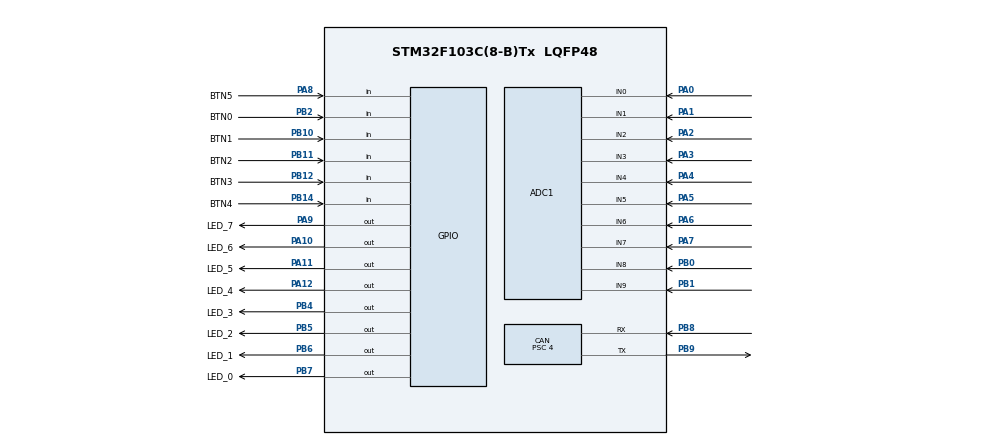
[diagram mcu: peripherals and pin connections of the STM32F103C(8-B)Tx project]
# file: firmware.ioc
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ADC1.Channel-0\#ChannelRegularConversion=ADC_CHANNEL_0
ADC1.Channel-1\#ChannelRegularConversion=ADC_CHANNEL_1
ADC1.Channel-10\#ChannelRegularConversion=ADC_CHANNEL_TEMPSENSOR
ADC1.Channel-2\#ChannelRegularConversion=ADC_CHANNEL_2
ADC1.Channel-3\#ChannelRegularConversion=ADC_CHANNEL_3
ADC1.Channel-4\#ChannelRegularConversion=ADC_CHANNEL_4
ADC1.Channel-5\#ChannelRegularConversion=ADC_CHANNEL_5
ADC1.Channel-6\#ChannelRegularConversion=ADC_CHANNEL_6
ADC1.Channel-7\#ChannelRegularConversion=ADC_CHANNEL_7
ADC1.Channel-8\#ChannelRegularConversion=ADC_CHANNEL_8
ADC1.Channel-9\#ChannelRegularConversion=ADC_CHANNEL_9
ADC1.NbrOfConversion=11
ADC1.NbrOfConversionFlag=1
ADC1.Rank-0\#ChannelRegularConversion=1
ADC1.Rank-1\#ChannelRegularConversion=2
ADC1.Rank-10\#ChannelRegularConversion=11
ADC1.Rank-2\#ChannelRegularConversion=3
ADC1.Rank-3\#ChannelRegularConversion=4
ADC1.Rank-4\#ChannelRegularConversion=5
ADC1.Rank-5\#ChannelRegularConversion=6
ADC1.Rank-6\#ChannelRegularConversion=7
ADC1.Rank-7\#ChannelRegularConversion=8
ADC1.Rank-8\#ChannelRegularConversion=9
ADC1.Rank-9\#ChannelRegularConversion=10
ADC1.SamplingTime-0\#ChannelRegularConversion=ADC_SAMPLETIME_71CYCLES_5
ADC1.SamplingTime-1\#ChannelRegularConversion=ADC_SAMPLETIME_71CYCLES_5
ADC1.SamplingTime-10\#ChannelRegularConversion=ADC_SAMPLETIME_239CYCLES_5
ADC1.SamplingTime-2\#ChannelRegularConversion=ADC_SAMPLETIME_71CYCLES_5
ADC1.SamplingTime-3\#ChannelRegularConversion=ADC_SAMPLETIME_71CYCLES_5
ADC1.SamplingTime-4\#ChannelRegularConversion=ADC_SAMPLETIME_71CYCLES_5
ADC1.SamplingTime-5\#ChannelRegularConversion=ADC_SAMPLETIME_71CYCLES_5
ADC1.SamplingTime-6\#ChannelRegularConversion=ADC_SAMPLETIME_71CYCLES_5
ADC1.SamplingTime-7\#ChannelRegularConversion=ADC_SAMPLETIME_71CYCLES_5
ADC1.SamplingTime-8\#ChannelRegularConversion=ADC_SAMPLETIME_71CYCLES_5
ADC1.SamplingTime-9\#ChannelRegularConversion=ADC_SAMPLETIME_71CYCLES_5
ADC1.master=1
CAN.BS1=CAN_BS1_11TQ
CAN.BS2=CAN_BS2_4TQ
CAN.CalculateBaudRate=500000
CAN.CalculateTimeBit=2000
CAN.CalculateTimeQuantum=125.0
CAN.Mode=CAN_MODE_NORMAL
CAN.NART=ENABLE
CAN.Prescaler=4
Dma.ADC1.0.Direction=DMA_PERIPH_TO_MEMORY
Dma.ADC1.0.Instance=DMA1_Channel1
Dma.ADC1.0.MemDataAlignment=DMA_MDATAALIGN_HALFWORD
Dma.ADC1.0.MemInc=DMA_MINC_ENABLE
Dma.ADC1.0.Mode=DMA_NORMAL
Dma.ADC1.0.PeriphDataAlignment=DMA_PDATAALIGN_HALFWORD
Dma.ADC1.0.PeriphInc=DMA_PINC_DISABLE
Dma.ADC1.0.Priority=DMA_PRIORITY_LOW
Dma.Request0=ADC1
Dma.Request1=TIM2_UP
Dma.Request2=TIM2_CH1
Dma.Request3=TIM2_CH2/CH4
Dma.TIM2_CH1.2.Direction=DMA_MEMORY_TO_PERIPH
Dma.TIM2_CH1.2.Instance=DMA1_Channel5
Dma.TIM2_CH1.2.MemDataAlignment=DMA_MDATAALIGN_HALFWORD
Dma.TIM2_CH1.2.MemInc=DMA_MINC_ENABLE
Dma.TIM2_CH1.2.Mode=DMA_NORMAL
Dma.TIM2_CH1.2.PeriphDataAlignment=DMA_PDATAALIGN_HALFWORD
Dma.TIM2_CH1.2.PeriphInc=DMA_PINC_DISABLE
Dma.TIM2_CH1.2.Priority=DMA_PRIORITY_VERY_HIGH
Dma.TIM2_CH2/CH4.3.Direction=DMA_MEMORY_TO_PERIPH
Dma.TIM2_CH2/CH4.3.Instance=DMA1_Channel7
Dma.TIM2_CH2/CH4.3.MemDataAlignment=DMA_MDATAALIGN_HALFWORD
Dma.TIM2_CH2/CH4.3.MemInc=DMA_MINC_DISABLE
Dma.TIM2_CH2/CH4.3.Mode=DMA_NORMAL
Dma.TIM2_CH2/CH4.3.PeriphDataAlignment=DMA_PDATAALIGN_HALFWORD
Dma.TIM2_CH2/CH4.3.PeriphInc=DMA_PINC_DISABLE
Dma.TIM2_CH2/CH4.3.Priority=DMA_PRIORITY_VERY_HIGH
Dma.TIM2_UP.1.Direction=DMA_MEMORY_TO_PERIPH
Dma.TIM2_UP.1.Instance=DMA1_Channel2
Dma.TIM2_UP.1.MemDataAlignment=DMA_MDATAALIGN_HALFWORD
Dma.TIM2_UP.1.MemInc=DMA_MINC_DISABLE
Dma.TIM2_UP.1.Mode=DMA_NORMAL
Dma.TIM2_UP.1.PeriphDataAlignment=DMA_PDATAALIGN_HALFWORD
Dma.TIM2_UP.1.PeriphInc=DMA_PINC_DISABLE
Dma.TIM2_UP.1.Priority=DMA_PRIORITY_VERY_HIGH
Mcu.Family=STM32F1
Mcu.Name=STM32F103C(8-B)Tx
Mcu.Package=LQFP48
NVIC.DMA1_Channel1_IRQn=true\:0\:0\:false\:false\:true\:false\:true\:true
NVIC.DMA1_Channel2_IRQn=true\:0\:0\:false\:false\:true\:false\:true\:true
NVIC.DMA1_Channel5_IRQn=true\:0\:0\:false\:false\:true\:false\:true\:true
NVIC.DMA1_Channel7_IRQn=true\:0\:0\:false\:false\:true\:false\:true\:true
NVIC.PriorityGroup=NVIC_PRIORITYGROUP_4
NVIC.USB_LP_CAN1_RX0_IRQn=true\:0\:0\:false\:false\:true\:true\:true\:true
PA0-WKUP.Signal=ADCx_IN0
PA1.Signal=ADCx_IN1
PA10.GPIO_Label=LED_6
PA10.GPIO_Speed=GPIO_SPEED_FREQ_HIGH
PA10.Signal=GPIO_Output
PA11.GPIO_Label=LED_5
PA11.GPIO_Speed=GPIO_SPEED_FREQ_HIGH
PA11.Signal=GPIO_Output
PA12.GPIO_Label=LED_4
PA12.GPIO_Speed=GPIO_SPEED_FREQ_HIGH
PA12.Signal=GPIO_Output
PA13.Mode=Trace_Asynchronous_SW
PA13.Signal=SYS_JTMS-SWDIO
PA14.Mode=Trace_Asynchronous_SW
PA14.Signal=SYS_JTCK-SWCLK
PA2.Signal=ADCx_IN2
PA3.Signal=ADCx_IN3
PA4.Signal=ADCx_IN4
PA5.Signal=ADCx_IN5
PA6.Signal=ADCx_IN6
PA7.Signal=ADCx_IN7
PA8.GPIO_Label=BTN5
PA8.Signal=GPIO_Input
PA9.GPIO_Label=LED_7
PA9.GPIO_Speed=GPIO_SPEED_FREQ_HIGH
PA9.Signal=GPIO_Output
PB0.Signal=ADCx_IN8
PB1.Signal=ADCx_IN9
PB10.GPIO_Label=BTN1
PB10.Signal=GPIO_Input
PB11.GPIO_Label=BTN2
PB11.Signal=GPIO_Input
PB12.GPIO_Label=BTN3
PB12.Signal=GPIO_Input
PB14.GPIO_Label=BTN4
PB14.Signal=GPIO_Input
PB2.GPIO_Label=BTN0
PB2.Signal=GPIO_Input
PB3.Mode=Trace_Asynchronous_SW
PB3.Signal=SYS_JTDO-TRACESWO
PB4.GPIO_Label=LED_3
PB4.GPIO_Speed=GPIO_SPEED_FREQ_HIGH
PB4.Signal=GPIO_Output
PB5.GPIO_Label=LED_2
PB5.GPIO_Speed=GPIO_SPEED_FREQ_HIGH
PB5.Signal=GPIO_Output
PB6.GPIO_Label=LED_1
PB6.GPIO_Speed=GPIO_SPEED_FREQ_HIGH
PB6.Signal=GPIO_Output
PB7.GPIO_Label=LED_0
PB7.GPIO_Speed=GPIO_SPEED_FREQ_HIGH
PB7.Signal=GPIO_Output
PB8.GPIO_Mode=GPIO_MODE_INPUT
PB8.GPIO_PuPd=GPIO_NOPULL
PB8.Mode=CAN_Activate
PB8.Signal=CAN_RX
PB9.Mode=CAN_Activate
PB9.Signal=CAN_TX
PD0-OSC_IN.Mode=HSE-External-Oscillator
PD0-OSC_IN.Signal=RCC_OSC_IN
PD1-OSC_OUT.Mode=HSE-External-Oscillator
PD1-OSC_OUT.Signal=RCC_OSC_OUT
ProjectManager.HeapSize=0x200
ProjectManager.StackSize=0x400
ProjectManager.TargetToolchain=Makefile
RCC.ADCPresc=RCC_ADCPCLK2_DIV6
RCC.AHBFreq_Value=128000000
RCC.APB1CLKDivider=RCC_HCLK_DIV4
RCC.APB1Freq_Value=32000000
RCC.APB1TimFreq_Value=64000000
RCC.APB2CLKDivider=RCC_HCLK_DIV2
RCC.APB2Freq_Value=64000000
RCC.APB2TimFreq_Value=128000000
RCC.HCLKFreq_Value=128000000
RCC.PLLMUL=RCC_PLL_MUL16
RCC.PLLSourceVirtual=RCC_PLLSOURCE_HSE
RCC.SYSCLKFreq_VALUE=128000000
RCC.SYSCLKSource=RCC_SYSCLKSOURCE_PLLCLK
RCC.USBFreq_Value=128000000
SH.ADCx_IN0.0=ADC1_IN0,IN0
SH.ADCx_IN1.0=ADC1_IN1,IN1
SH.ADCx_IN2.0=ADC1_IN2,IN2
SH.ADCx_IN3.0=ADC1_IN3,IN3
SH.ADCx_IN4.0=ADC1_IN4,IN4
SH.ADCx_IN5.0=ADC1_IN5,IN5
SH.ADCx_IN6.0=ADC1_IN6,IN6
SH.ADCx_IN7.0=ADC1_IN7,IN7
SH.ADCx_IN8.0=ADC1_IN8,IN8
SH.ADCx_IN9.0=ADC1_IN9,IN9
TIM2.AutoReloadPreload=TIM_AUTORELOAD_PRELOAD_ENABLE
TIM2.Channel-PWM\ Generation1\ No\ Output=TIM_CHANNEL_1
TIM2.Channel-PWM\ Generation2\ No\ Output=TIM_CHANNEL_2
TIM2.Period=76
TIM2.Pulse-PWM\ Generation1\ No\ Output=10
TIM2.Pulse-PWM\ Generation2\ No\ Output=41
VP_ADC1_TempSens_Input.Mode=IN-TempSens
VP_TIM2_VS_ClockSourceINT.Mode=Internal
VP_TIM2_VS_no_output1.Mode=PWM Generation1 No Output
VP_TIM2_VS_no_output2.Mode=PWM Generation2 No Output
board=custom

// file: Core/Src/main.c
/* USER CODE BEGIN Header */
/**
  ******************************************************************************
  * @file           : main.c
  * @brief          : Main program body - EV Dashboard 2026
  ******************************************************************************
  * @attention
  *
  * Copyright (c) 2023 STMicroelectronics.
  * All rights reserved.
  *
  * This software is licensed under terms that can be found in the LICENSE file
  * in the root directory of this software component.
  * If no LICENSE file comes with this software, it is provided AS-IS.
  *
  ******************************************************************************
  */
/* USER CODE END Header */
#include "main.h"

/* USER CODE BEGIN Includes */

#include <math.h>

#include "ws2812.h"
#include "display.h"
#include "auto_brightness.h"
#include "dial.h"
#include "ui.h"
#include "can-ids/CAN.h"
/* USER CODE END Includes */

ADC_HandleTypeDef hadc1;
DMA_HandleTypeDef hdma_adc1;

CAN_HandleTypeDef hcan;

TIM_HandleTypeDef htim2;
DMA_HandleTypeDef hdma_tim2_up;
DMA_HandleTypeDef hdma_tim2_ch1;
DMA_HandleTypeDef hdma_tim2_ch2_ch4;

/* USER CODE BEGIN PV */

volatile uint16_t adc_buffer[2][11];
volatile uint8_t adc_buffer_idx = 0;
volatile uint8_t adc_ready = 1;
struct CarState carState;
/* USER CODE END PV */

void SystemClock_Config(void);
static void MX_GPIO_Init(void);
static void MX_DMA_Init(void);
static void MX_CAN_Init(void);
static void MX_ADC1_Init(void);
static void MX_TIM2_Init(void);
/* USER CODE BEGIN PFP */
extern void HAL_ADC_ConvCpltCallback(ADC_HandleTypeDef* hadc);
/* USER CODE END PFP */

/* USER CODE BEGIN 0 */

void can_irq(CAN_HandleTypeDef *pcan) {
  CAN_RxHeaderTypeDef msg;
    uint8_t data[8];
    HAL_CAN_GetRxMessage(pcan, CAN_RX_FIFO0, &msg, data);

    if (msg.IDE == CAN_ID_STD) {
        switch (msg.StdId) {
            // ===== INVERTER MESSAGES =====

            case INVERTER_HIGH_SPEED_ID:
                // High-speed frame (3ms) - most important data
                carState.commanded_torque = read_field_i16(&INVERTER_HIGH_SPEED_commanded_torque, data);
                carState.torque_feedback = read_field_i16(&INVERTER_HIGH_SPEED_torque_feedback, data);
                carState.motor_speed = read_field_i16(&INVERTER_HIGH_SPEED_motor_speed, data);
                carState.dc_bus_voltage = read_field_i16(&INVERTER_HIGH_SPEED_dc_bus_voltage, data);
                carState.last_inverter_msg_tick = HAL_GetTick();
                break;

            case INVERTER_TEMP_1_ID:
                // IGBT temperatures
                carState.igbt_a_temp = read_field_i16(&INVERTER_TEMP_1_IGBT_A_temp, data);
                carState.igbt_b_temp = read_field_i16(&INVERTER_TEMP_1_IGBT_B_temp, data);
                carState.igbt_c_temp = read_field_i16(&INVERTER_TEMP_1_IGBT_C_temp, data);
                carState.gate_driver_temp = read_field_i16(&INVERTER_TEMP_1_gate_driver_temp, data);
                break;

            case INVERTER_TEMP_2_ID:
                // Control board and RTD temperatures
                carState.control_board_temp = read_field_i16(&INVERTER_TEMP_2_control_board_temp, data);
                // RTD temps available if needed
                break;

            case INVERTER_TEMP_3_ID:
                // Motor temperature
                carState.motor_temp = read_field_i16(&INVERTER_TEMP_3_motor_temp, data);
                break;

            case INVERTER_CURRENT_ID:
                // DC bus current
                carState.dc_bus_current = read_field_i16(&INVERTER_CURRENT_dc_bus, data);
                break;

            case INVERTER_INTERNAL_VOLTAGE_ID:
                // 12V (GLV) voltage
                carState.glv_voltage = read_field_i16(&INVERTER_INTERNAL_VOLTAGE_glv_voltage, data);
                break;

            case INVERTER_INTERNAL_STATES_ID:
                // Inverter state machine
                carState.vsm_state = read_field_u8(&INVERTER_INTERNAL_STATES_vsm_state, data);
                carState.inverter_state = read_field_u8(&INVERTER_INTERNAL_STATES_inverter_state, data);
                carState.inverter_enable = read_field_u8(&INVERTER_INTERNAL_STATES_enable_state, data);
                carState.direction_command = read_field_u8(&INVERTER_INTERNAL_STATES_direction_command, data);
                carState.run_mode = read_field_u8(&INVERTER_INTERNAL_STATES_run_mode, data);
                break;

            case INVERTER_FAULT_CODES_ID:
                // Fault codes
                carState.post_fault = read_field_u32(&INVERTER_FAULT_CODES_POST_fault, data);
                carState.run_fault = read_field_u32(&INVERTER_FAULT_CODES_run_fault, data);
                break;

                // ===== ORION BMS MESSAGES =====

            case BMS_PACK_STATUS_ID:
                // Pack SOC, Voltage, Current
                carState.soc_percent = read_field_u8(&BMS_PACK_STATUS_pack_soc, data);
                carState.pack_voltage = read_field_u16(&BMS_PACK_STATUS_pack_voltage, data);
                carState.pack_current = read_field_i16(&BMS_PACK_STATUS_pack_current, data);
                carState.last_bms_msg_tick = HAL_GetTick();
                break;

            case BMS_TEMPS_ID:
                // Battery temperatures
                carState.pack_temp_max = read_field_i16(&BMS_TEMPS_max_cell_temp, data);
                carState.pack_temp_min = read_field_i16(&BMS_TEMPS_min_cell_temp, data);
                break;

            case BMS_STATUS_ID:
                // BMS status and limits
                carState.bms_fault_code = read_field_u8(&BMS_STATUS_fault_code, data);
                // Pack discharge/charge limits available here if needed
                break;

            // ===== DASHBOARD INPUTS (from steering wheel) =====

            case DASHBOARD_0_ID:
                carState.dial_pos[0] = read_field_u8(&DASHBOARD_0_dial_0, data);
                carState.dial_pos[1] = read_field_u8(&DASHBOARD_0_dial_1, data);
                break;

            // ===== BOOTLOADER =====

            case BOOTLOADER_ID:
                // Reset to bootloader if requested
                __NVIC_SystemReset();
                break;

            default:
                // Unknown message

        break;
      }
  }
}

void HAL_ADC_ConvCpltCallback(ADC_HandleTypeDef* hadc){
  /* This is called after the conversion is completed */
  adc_buffer_idx = (adc_buffer_idx + 1) % 2;
  adc_ready = 1;
}

/* USER CODE END 0 */

int main(void)
{
  /* USER CODE BEGIN 1 */
  // relocate vector table to work with bootloader
	SCB->VTOR = (uint32_t)0x08003000;
  /* USER CODE END 1 */

  /* MCU Configuration--------------------------------------------------------*/

  /* Reset of all peripherals, Initializes the Flash interface and the Systick. */
  HAL_Init();

  /* Configure the system clock */
  SystemClock_Config();

  /* Initialize all configured peripherals */
  MX_GPIO_Init();
  MX_DMA_Init();
  MX_CAN_Init();
  MX_ADC1_Init();
  MX_TIM2_Init();
  /* USER CODE BEGIN 2 */

  HAL_ADCEx_Calibration_Start(&hadc1);

  // Initialize car state to safe defaults
    carState.soc_percent = 50;  // Will be updated by BMS
    carState.drive_mode = 1;    // Normal mode
    carState.last_inverter_msg_tick = HAL_GetTick();
    carState.last_bms_msg_tick = HAL_GetTick();

    // Initialize UI
    init_ui(); // includes startup animation
  /* USER CODE END 2 */

  /* Infinite loop */
  /* USER CODE BEGIN WHILE */
  while (1)
  {

        /* USER CODE BEGIN WHILE */

        // Start ADC conversion
        if (adc_ready) {
            uint8_t new_idx = (adc_buffer_idx + 1) % 2;
            HAL_ADC_Start_DMA(&hadc1, (uint32_t *)adc_buffer[new_idx], 11);
            adc_ready = 0;
        }

        // ~100Hz main loop
        HAL_Delay(10);

        // Update brightness from ambient light sensor
        update_brightness(adc_buffer[adc_buffer_idx][9]);

        // Update dial positions from ADC
        update_dial_state(adc_buffer[adc_buffer_idx][0],
                         adc_buffer[adc_buffer_idx][1]);

        // Update UI (this replaces the manual display code)
        update_ui();

        /* USER CODE END WHILE */
    }
}

void SystemClock_Config(void)
{
  RCC_OscInitTypeDef RCC_OscInitStruct = {0};
  RCC_ClkInitTypeDef RCC_ClkInitStruct = {0};
  RCC_PeriphCLKInitTypeDef PeriphClkInit = {0};

  /** Initializes the RCC Oscillators according to the specified parameters
  * in the RCC_OscInitTypeDef structure.
  */
  RCC_OscInitStruct.OscillatorType = RCC_OSCILLATORTYPE_HSE;
  RCC_OscInitStruct.HSEState = RCC_HSE_ON;
  RCC_OscInitStruct.HSEPredivValue = RCC_HSE_PREDIV_DIV1;
  RCC_OscInitStruct.HSIState = RCC_HSI_ON;
  RCC_OscInitStruct.PLL.PLLState = RCC_PLL_ON;
  RCC_OscInitStruct.PLL.PLLSource = RCC_PLLSOURCE_HSE;
  RCC_OscInitStruct.PLL.PLLMUL = RCC_PLL_MUL9;
  if (HAL_RCC_OscConfig(&RCC_OscInitStruct) != HAL_OK)
  {
    Error_Handler();
  }

  /** Initializes the CPU, AHB and APB buses clocks
  */
  RCC_ClkInitStruct.ClockType = RCC_CLOCKTYPE_HCLK|RCC_CLOCKTYPE_SYSCLK
                              |RCC_CLOCKTYPE_PCLK1|RCC_CLOCKTYPE_PCLK2;
  RCC_ClkInitStruct.SYSCLKSource = RCC_SYSCLKSOURCE_PLLCLK;
  RCC_ClkInitStruct.AHBCLKDivider = RCC_SYSCLK_DIV1;
  RCC_ClkInitStruct.APB1CLKDivider = RCC_HCLK_DIV2;
  RCC_ClkInitStruct.APB2CLKDivider = RCC_HCLK_DIV1;

  if (HAL_RCC_ClockConfig(&RCC_ClkInitStruct, FLASH_LATENCY_2) != HAL_OK)
  {
    Error_Handler();
  }
  PeriphClkInit.PeriphClockSelection = RCC_PERIPHCLK_ADC;
  PeriphClkInit.AdcClockSelection = RCC_ADCPCLK2_DIV6;
  if (HAL_RCCEx_PeriphCLKConfig(&PeriphClkInit) != HAL_OK)
  {
    Error_Handler();
  }
}

static void MX_ADC1_Init(void)
{

  ADC_ChannelConfTypeDef sConfig = {0};

  /** Common config
  */
  hadc1.Instance = ADC1;
  hadc1.Init.ScanConvMode = ADC_SCAN_ENABLE;
  hadc1.Init.ContinuousConvMode = DISABLE;
  hadc1.Init.DiscontinuousConvMode = DISABLE;
  hadc1.Init.ExternalTrigConv = ADC_SOFTWARE_START;
  hadc1.Init.DataAlign = ADC_DATAALIGN_RIGHT;
  hadc1.Init.NbrOfConversion = 11;
  if (HAL_ADC_Init(&hadc1) != HAL_OK)
  {
    Error_Handler();
  }

  /** Configure Regular Channel
  */
  sConfig.Channel = ADC_CHANNEL_0;
  sConfig.Rank = ADC_REGULAR_RANK_1;
  sConfig.SamplingTime = ADC_SAMPLETIME_71CYCLES_5;
  if (HAL_ADC_ConfigChannel(&hadc1, &sConfig) != HAL_OK)
  {
    Error_Handler();
  }

  /** Configure Regular Channel
  */
  sConfig.Channel = ADC_CHANNEL_1;
  sConfig.Rank = ADC_REGULAR_RANK_2;
  if (HAL_ADC_ConfigChannel(&hadc1, &sConfig) != HAL_OK)
  {
    Error_Handler();
  }

  /** Configure Regular Channel
  */
  sConfig.Channel = ADC_CHANNEL_2;
  sConfig.Rank = ADC_REGULAR_RANK_3;
  if (HAL_ADC_ConfigChannel(&hadc1, &sConfig) != HAL_OK)
  {
    Error_Handler();
  }

  /** Configure Regular Channel
  */
  sConfig.Channel = ADC_CHANNEL_3;
  sConfig.Rank = ADC_REGULAR_RANK_4;
  if (HAL_ADC_ConfigChannel(&hadc1, &sConfig) != HAL_OK)
  {
    Error_Handler();
  }

  /** Configure Regular Channel
  */
  sConfig.Channel = ADC_CHANNEL_4;
  sConfig.Rank = ADC_REGULAR_RANK_5;
  if (HAL_ADC_ConfigChannel(&hadc1, &sConfig) != HAL_OK)
  {
    Error_Handler();
  }

  /** Configure Regular Channel
  */
  sConfig.Channel = ADC_CHANNEL_5;
  sConfig.Rank = ADC_REGULAR_RANK_6;
  if (HAL_ADC_ConfigChannel(&hadc1, &sConfig) != HAL_OK)
  {
    Error_Handler();
  }

  /** Configure Regular Channel
  */
  sConfig.Channel = ADC_CHANNEL_6;
  sConfig.Rank = ADC_REGULAR_RANK_7;
  if (HAL_ADC_ConfigChannel(&hadc1, &sConfig) != HAL_OK)
  {
    Error_Handler();
  }

  /** Configure Regular Channel
  */
  sConfig.Channel = ADC_CHANNEL_7;
  sConfig.Rank = ADC_REGULAR_RANK_8;
  if (HAL_ADC_ConfigChannel(&hadc1, &sConfig) != HAL_OK)
  {
    Error_Handler();
  }

  /** Configure Regular Channel
  */
  sConfig.Channel = ADC_CHANNEL_8;
  sConfig.Rank = ADC_REGULAR_RANK_9;
  if (HAL_ADC_ConfigChannel(&hadc1, &sConfig) != HAL_OK)
  {
    Error_Handler();
  }

  /** Configure Regular Channel
  */
  sConfig.Channel = ADC_CHANNEL_9;
  sConfig.Rank = ADC_REGULAR_RANK_10;
  if (HAL_ADC_ConfigChannel(&hadc1, &sConfig) != HAL_OK)
  {
    Error_Handler();
  }

  /** Configure Regular Channel
  */
  sConfig.Channel = ADC_CHANNEL_TEMPSENSOR;
  sConfig.Rank = ADC_REGULAR_RANK_11;
  sConfig.SamplingTime = ADC_SAMPLETIME_239CYCLES_5;
  if (HAL_ADC_ConfigChannel(&hadc1, &sConfig) != HAL_OK)
  {
    Error_Handler();
  }

}

static void MX_CAN_Init(void)
{

  hcan.Instance = CAN1;
  hcan.Init.Prescaler = 4;
  hcan.Init.Mode = CAN_MODE_NORMAL;
  hcan.Init.SyncJumpWidth = CAN_SJW_1TQ;
  hcan.Init.TimeSeg1 = CAN_BS1_11TQ;
  hcan.Init.TimeSeg2 = CAN_BS2_4TQ;
  hcan.Init.TimeTriggeredMode = DISABLE;
  hcan.Init.AutoBusOff = DISABLE;
  hcan.Init.AutoWakeUp = DISABLE;
  hcan.Init.AutoRetransmission = ENABLE;
  hcan.Init.ReceiveFifoLocked = DISABLE;
  hcan.Init.TransmitFifoPriority = DISABLE;
  if (HAL_CAN_Init(&hcan) != HAL_OK)
  {
    Error_Handler();
  }
  /* USER CODE BEGIN CAN_Init 2 */
  // Accept all CAN messages
  CAN_FilterTypeDef sf;

  // First filter - ECU messages
  sf.FilterMaskIdHigh = 0x700 << 5; // Filter by top 3 bits
  sf.FilterIdHigh = 0x0A0 << 5;

  // Second filter - Bootloader requests
  sf.FilterMaskIdLow = 0x7FF << 5;
  sf.FilterIdLow = 0x6B0 << 5;

  // Filters into CAN FIFO 0
  sf.FilterFIFOAssignment = CAN_FILTER_FIFO0;
  // Filter settings
  sf.FilterBank = 0;
  sf.FilterMode = CAN_FILTERMODE_IDMASK; // ID/Mask mode (rather than ID list)
  sf.FilterScale = CAN_FILTERSCALE_16BIT; // two 16 bit filters
  sf.FilterActivation = CAN_FILTER_ENABLE;

  if (HAL_CAN_ConfigFilter(&hcan, &sf) != HAL_OK) {
    Error_Handler();
  }

  if (HAL_CAN_RegisterCallback(&hcan, HAL_CAN_RX_FIFO0_MSG_PENDING_CB_ID, can_irq)) {
    Error_Handler();
  }

  if (HAL_CAN_Start(&hcan) != HAL_OK) {
    Error_Handler();
  }

  if (HAL_CAN_ActivateNotification(&hcan, CAN_IT_RX_FIFO0_MSG_PENDING) != HAL_OK) {
    Error_Handler();
  }

  /* USER CODE END CAN_Init 2 */

}

static void MX_TIM2_Init(void)
{

  TIM_ClockConfigTypeDef sClockSourceConfig = {0};
  TIM_MasterConfigTypeDef sMasterConfig = {0};
  TIM_OC_InitTypeDef sConfigOC = {0};

  htim2.Instance = TIM2;
  htim2.Init.Prescaler = 0;
  htim2.Init.CounterMode = TIM_COUNTERMODE_UP;
  htim2.Init.Period = 90;
  htim2.Init.ClockDivision = TIM_CLOCKDIVISION_DIV1;
  htim2.Init.AutoReloadPreload = TIM_AUTORELOAD_PRELOAD_ENABLE;
  if (HAL_TIM_Base_Init(&htim2) != HAL_OK)
  {
    Error_Handler();
  }
  sClockSourceConfig.ClockSource = TIM_CLOCKSOURCE_INTERNAL;
  if (HAL_TIM_ConfigClockSource(&htim2, &sClockSourceConfig) != HAL_OK)
  {
    Error_Handler();
  }
  if (HAL_TIM_PWM_Init(&htim2) != HAL_OK)
  {
    Error_Handler();
  }
  sMasterConfig.MasterOutputTrigger = TIM_TRGO_RESET;
  sMasterConfig.MasterSlaveMode = TIM_MASTERSLAVEMODE_DISABLE;
  if (HAL_TIMEx_MasterConfigSynchronization(&htim2, &sMasterConfig) != HAL_OK)
  {
    Error_Handler();
  }
  sConfigOC.OCMode = TIM_OCMODE_PWM1;
  sConfigOC.Pulse = 29;
  sConfigOC.OCPolarity = TIM_OCPOLARITY_HIGH;
  sConfigOC.OCFastMode = TIM_OCFAST_DISABLE;
  if (HAL_TIM_PWM_ConfigChannel(&htim2, &sConfigOC, TIM_CHANNEL_1) != HAL_OK)
  {
    Error_Handler();
  }
  sConfigOC.Pulse = 58;
  if (HAL_TIM_PWM_ConfigChannel(&htim2, &sConfigOC, TIM_CHANNEL_2) != HAL_OK)
  {
    Error_Handler();
  }

}

static void MX_DMA_Init(void)
{

  /* DMA controller clock enable */
  __HAL_RCC_DMA1_CLK_ENABLE();

  /* DMA interrupt init */
  /* DMA1_Channel1_IRQn interrupt configuration */
  HAL_NVIC_SetPriority(DMA1_Channel1_IRQn, 0, 0);
  HAL_NVIC_EnableIRQ(DMA1_Channel1_IRQn);
  /* DMA1_Channel2_IRQn interrupt configuration */
  HAL_NVIC_SetPriority(DMA1_Channel2_IRQn, 0, 0);
  HAL_NVIC_EnableIRQ(DMA1_Channel2_IRQn);
  /* DMA1_Channel5_IRQn interrupt configuration */
  HAL_NVIC_SetPriority(DMA1_Channel5_IRQn, 0, 0);
  HAL_NVIC_EnableIRQ(DMA1_Channel5_IRQn);
  /* DMA1_Channel7_IRQn interrupt configuration */
  HAL_NVIC_SetPriority(DMA1_Channel7_IRQn, 0, 0);
  HAL_NVIC_EnableIRQ(DMA1_Channel7_IRQn);

}

static void MX_GPIO_Init(void)
{
  GPIO_InitTypeDef GPIO_InitStruct = {0};

  /* GPIO Ports Clock Enable */
  __HAL_RCC_GPIOD_CLK_ENABLE();
  __HAL_RCC_GPIOA_CLK_ENABLE();
  __HAL_RCC_GPIOB_CLK_ENABLE();

  /*Configure GPIO pin Output Level */
  HAL_GPIO_WritePin(GPIOA, LED_7_Pin|LED_6_Pin|LED_5_Pin|LED_4_Pin, GPIO_PIN_RESET);

  /*Configure GPIO pin Output Level */
  HAL_GPIO_WritePin(GPIOB, LED_3_Pin|LED_2_Pin|LED_1_Pin|LED_0_Pin, GPIO_PIN_RESET);

  /*Configure GPIO pins : BTN0_Pin BTN1_Pin BTN2_Pin BTN3_Pin
                           BTN4_Pin */
  GPIO_InitStruct.Pin = BTN0_Pin|BTN1_Pin|BTN2_Pin|BTN3_Pin
                          |BTN4_Pin;
  GPIO_InitStruct.Mode = GPIO_MODE_INPUT;
  GPIO_InitStruct.Pull = GPIO_NOPULL;
  HAL_GPIO_Init(GPIOB, &GPIO_InitStruct);

  /*Configure GPIO pin : BTN5_Pin */
  GPIO_InitStruct.Pin = BTN5_Pin;
  GPIO_InitStruct.Mode = GPIO_MODE_INPUT;
  GPIO_InitStruct.Pull = GPIO_NOPULL;
  HAL_GPIO_Init(BTN5_GPIO_Port, &GPIO_InitStruct);

  /*Configure GPIO pins : LED_7_Pin LED_6_Pin LED_5_Pin LED_4_Pin */
  GPIO_InitStruct.Pin = LED_7_Pin|LED_6_Pin|LED_5_Pin|LED_4_Pin;
  GPIO_InitStruct.Mode = GPIO_MODE_OUTPUT_PP;
  GPIO_InitStruct.Pull = GPIO_NOPULL;
  GPIO_InitStruct.Speed = GPIO_SPEED_FREQ_HIGH;
  HAL_GPIO_Init(GPIOA, &GPIO_InitStruct);

  /*Configure GPIO pins : LED_3_Pin LED_2_Pin LED_1_Pin LED_0_Pin */
  GPIO_InitStruct.Pin = LED_3_Pin|LED_2_Pin|LED_1_Pin|LED_0_Pin;
  GPIO_InitStruct.Mode = GPIO_MODE_OUTPUT_PP;
  GPIO_InitStruct.Pull = GPIO_NOPULL;
  GPIO_InitStruct.Speed = GPIO_SPEED_FREQ_HIGH;
  HAL_GPIO_Init(GPIOB, &GPIO_InitStruct);

}

void Error_Handler(void)
{
  __disable_irq();
  while (1)
  {
  }
}
